VERSION 5.7 ;
BUSBITCHARS "[]" ;
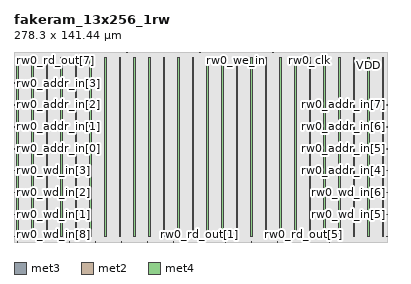
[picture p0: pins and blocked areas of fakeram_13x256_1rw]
MACRO fakeram_13x256_1rw
  FOREIGN fakeram_13x256_1rw 0 0 ;
  SYMMETRY X Y R90 ;
  SIZE 278.300 BY 141.440 ;
  CLASS BLOCK ;
  PIN rw0_wd_in[0]
    DIRECTION INPUT ;
    USE SIGNAL ;
    SHAPE ABUTMENT ;
    PORT
      LAYER met3 ;
      RECT 0.000 3.930 0.900 4.230 ;
    END
  END rw0_wd_in[0]
  PIN rw0_wd_in[1]
    DIRECTION INPUT ;
    USE SIGNAL ;
    SHAPE ABUTMENT ;
    PORT
      LAYER met3 ;
      RECT 0.000 20.250 0.900 20.550 ;
    END
  END rw0_wd_in[1]
  PIN rw0_wd_in[2]
    DIRECTION INPUT ;
    USE SIGNAL ;
    SHAPE ABUTMENT ;
    PORT
      LAYER met3 ;
      RECT 0.000 36.570 0.900 36.870 ;
    END
  END rw0_wd_in[2]
  PIN rw0_wd_in[3]
    DIRECTION INPUT ;
    USE SIGNAL ;
    SHAPE ABUTMENT ;
    PORT
      LAYER met3 ;
      RECT 0.000 52.890 0.900 53.190 ;
    END
  END rw0_wd_in[3]
  PIN rw0_wd_in[4]
    DIRECTION INPUT ;
    USE SIGNAL ;
    SHAPE ABUTMENT ;
    PORT
      LAYER met3 ;
      RECT 277.400 3.930 278.300 4.230 ;
    END
  END rw0_wd_in[4]
  PIN rw0_wd_in[5]
    DIRECTION INPUT ;
    USE SIGNAL ;
    SHAPE ABUTMENT ;
    PORT
      LAYER met3 ;
      RECT 277.400 20.250 278.300 20.550 ;
    END
  END rw0_wd_in[5]
  PIN rw0_wd_in[6]
    DIRECTION INPUT ;
    USE SIGNAL ;
    SHAPE ABUTMENT ;
    PORT
      LAYER met3 ;
      RECT 277.400 36.570 278.300 36.870 ;
    END
  END rw0_wd_in[6]
  PIN rw0_wd_in[7]
    DIRECTION INPUT ;
    USE SIGNAL ;
    SHAPE ABUTMENT ;
    PORT
      LAYER met2 ;
      RECT 2.690 0.000 2.830 0.420 ;
    END
  END rw0_wd_in[7]
  PIN rw0_wd_in[8]
    DIRECTION INPUT ;
    USE SIGNAL ;
    SHAPE ABUTMENT ;
    PORT
      LAYER met2 ;
      RECT 22.010 0.000 22.150 0.420 ;
    END
  END rw0_wd_in[8]
  PIN rw0_wd_in[9]
    DIRECTION INPUT ;
    USE SIGNAL ;
    SHAPE ABUTMENT ;
    PORT
      LAYER met2 ;
      RECT 41.330 0.000 41.470 0.420 ;
    END
  END rw0_wd_in[9]
  PIN rw0_wd_in[10]
    DIRECTION INPUT ;
    USE SIGNAL ;
    SHAPE ABUTMENT ;
    PORT
      LAYER met2 ;
      RECT 60.650 0.000 60.790 0.420 ;
    END
  END rw0_wd_in[10]
  PIN rw0_wd_in[11]
    DIRECTION INPUT ;
    USE SIGNAL ;
    SHAPE ABUTMENT ;
    PORT
      LAYER met2 ;
      RECT 79.970 0.000 80.110 0.420 ;
    END
  END rw0_wd_in[11]
  PIN rw0_wd_in[12]
    DIRECTION INPUT ;
    USE SIGNAL ;
    SHAPE ABUTMENT ;
    PORT
      LAYER met2 ;
      RECT 99.290 0.000 99.430 0.420 ;
    END
  END rw0_wd_in[12]
  PIN rw0_rd_out[0]
    DIRECTION OUTPUT ;
    USE SIGNAL ;
    SHAPE ABUTMENT ;
    PORT
      LAYER met2 ;
      RECT 118.610 0.000 118.750 0.420 ;
    END
  END rw0_rd_out[0]
  PIN rw0_rd_out[1]
    DIRECTION OUTPUT ;
    USE SIGNAL ;
    SHAPE ABUTMENT ;
    PORT
      LAYER met2 ;
      RECT 137.930 0.000 138.070 0.420 ;
    END
  END rw0_rd_out[1]
  PIN rw0_rd_out[2]
    DIRECTION OUTPUT ;
    USE SIGNAL ;
    SHAPE ABUTMENT ;
    PORT
      LAYER met2 ;
      RECT 157.250 0.000 157.390 0.420 ;
    END
  END rw0_rd_out[2]
  PIN rw0_rd_out[3]
    DIRECTION OUTPUT ;
    USE SIGNAL ;
    SHAPE ABUTMENT ;
    PORT
      LAYER met2 ;
      RECT 176.570 0.000 176.710 0.420 ;
    END
  END rw0_rd_out[3]
  PIN rw0_rd_out[4]
    DIRECTION OUTPUT ;
    USE SIGNAL ;
    SHAPE ABUTMENT ;
    PORT
      LAYER met2 ;
      RECT 195.890 0.000 196.030 0.420 ;
    END
  END rw0_rd_out[4]
  PIN rw0_rd_out[5]
    DIRECTION OUTPUT ;
    USE SIGNAL ;
    SHAPE ABUTMENT ;
    PORT
      LAYER met2 ;
      RECT 215.210 0.000 215.350 0.420 ;
    END
  END rw0_rd_out[5]
  PIN rw0_rd_out[6]
    DIRECTION OUTPUT ;
    USE SIGNAL ;
    SHAPE ABUTMENT ;
    PORT
      LAYER met2 ;
      RECT 234.530 0.000 234.670 0.420 ;
    END
  END rw0_rd_out[6]
  PIN rw0_rd_out[7]
    DIRECTION OUTPUT ;
    USE SIGNAL ;
    SHAPE ABUTMENT ;
    PORT
      LAYER met2 ;
      RECT 2.690 141.020 2.830 141.440 ;
    END
  END rw0_rd_out[7]
  PIN rw0_rd_out[8]
    DIRECTION OUTPUT ;
    USE SIGNAL ;
    SHAPE ABUTMENT ;
    PORT
      LAYER met2 ;
      RECT 29.830 141.020 29.970 141.440 ;
    END
  END rw0_rd_out[8]
  PIN rw0_rd_out[9]
    DIRECTION OUTPUT ;
    USE SIGNAL ;
    SHAPE ABUTMENT ;
    PORT
      LAYER met2 ;
      RECT 56.970 141.020 57.110 141.440 ;
    END
  END rw0_rd_out[9]
  PIN rw0_rd_out[10]
    DIRECTION OUTPUT ;
    USE SIGNAL ;
    SHAPE ABUTMENT ;
    PORT
      LAYER met2 ;
      RECT 84.110 141.020 84.250 141.440 ;
    END
  END rw0_rd_out[10]
  PIN rw0_rd_out[11]
    DIRECTION OUTPUT ;
    USE SIGNAL ;
    SHAPE ABUTMENT ;
    PORT
      LAYER met2 ;
      RECT 111.250 141.020 111.390 141.440 ;
    END
  END rw0_rd_out[11]
  PIN rw0_rd_out[12]
    DIRECTION OUTPUT ;
    USE SIGNAL ;
    SHAPE ABUTMENT ;
    PORT
      LAYER met2 ;
      RECT 138.390 141.020 138.530 141.440 ;
    END
  END rw0_rd_out[12]
  PIN rw0_addr_in[0]
    DIRECTION INPUT ;
    USE SIGNAL ;
    SHAPE ABUTMENT ;
    PORT
      LAYER met3 ;
      RECT 0.000 69.210 0.900 69.510 ;
    END
  END rw0_addr_in[0]
  PIN rw0_addr_in[1]
    DIRECTION INPUT ;
    USE SIGNAL ;
    SHAPE ABUTMENT ;
    PORT
      LAYER met3 ;
      RECT 0.000 85.530 0.900 85.830 ;
    END
  END rw0_addr_in[1]
  PIN rw0_addr_in[2]
    DIRECTION INPUT ;
    USE SIGNAL ;
    SHAPE ABUTMENT ;
    PORT
      LAYER met3 ;
      RECT 0.000 101.850 0.900 102.150 ;
    END
  END rw0_addr_in[2]
  PIN rw0_addr_in[3]
    DIRECTION INPUT ;
    USE SIGNAL ;
    SHAPE ABUTMENT ;
    PORT
      LAYER met3 ;
      RECT 0.000 118.170 0.900 118.470 ;
    END
  END rw0_addr_in[3]
  PIN rw0_addr_in[4]
    DIRECTION INPUT ;
    USE SIGNAL ;
    SHAPE ABUTMENT ;
    PORT
      LAYER met3 ;
      RECT 277.400 52.890 278.300 53.190 ;
    END
  END rw0_addr_in[4]
  PIN rw0_addr_in[5]
    DIRECTION INPUT ;
    USE SIGNAL ;
    SHAPE ABUTMENT ;
    PORT
      LAYER met3 ;
      RECT 277.400 69.210 278.300 69.510 ;
    END
  END rw0_addr_in[5]
  PIN rw0_addr_in[6]
    DIRECTION INPUT ;
    USE SIGNAL ;
    SHAPE ABUTMENT ;
    PORT
      LAYER met3 ;
      RECT 277.400 85.530 278.300 85.830 ;
    END
  END rw0_addr_in[6]
  PIN rw0_addr_in[7]
    DIRECTION INPUT ;
    USE SIGNAL ;
    SHAPE ABUTMENT ;
    PORT
      LAYER met3 ;
      RECT 277.400 101.850 278.300 102.150 ;
    END
  END rw0_addr_in[7]
  PIN rw0_we_in
    DIRECTION INPUT ;
    USE SIGNAL ;
    SHAPE ABUTMENT ;
    PORT
      LAYER met2 ;
      RECT 165.530 141.020 165.670 141.440 ;
    END
  END rw0_we_in
  PIN rw0_ce_in
    DIRECTION INPUT ;
    USE SIGNAL ;
    SHAPE ABUTMENT ;
    PORT
      LAYER met2 ;
      RECT 192.670 141.020 192.810 141.440 ;
    END
  END rw0_ce_in
  PIN rw0_clk
    DIRECTION INPUT ;
    USE SIGNAL ;
    SHAPE ABUTMENT ;
    PORT
      LAYER met2 ;
      RECT 219.810 141.020 219.950 141.440 ;
    END
  END rw0_clk
  PIN VSS
    DIRECTION INOUT ;
    USE GROUND ;
    PORT
      LAYER met4 ;
      RECT 2.160 4.080 3.360 137.360 ;
      RECT 13.040 4.080 14.240 137.360 ;
      RECT 23.920 4.080 25.120 137.360 ;
      RECT 34.800 4.080 36.000 137.360 ;
      RECT 45.680 4.080 46.880 137.360 ;
      RECT 56.560 4.080 57.760 137.360 ;
      RECT 67.440 4.080 68.640 137.360 ;
      RECT 78.320 4.080 79.520 137.360 ;
      RECT 89.200 4.080 90.400 137.360 ;
      RECT 100.080 4.080 101.280 137.360 ;
      RECT 110.960 4.080 112.160 137.360 ;
      RECT 121.840 4.080 123.040 137.360 ;
      RECT 132.720 4.080 133.920 137.360 ;
      RECT 143.600 4.080 144.800 137.360 ;
      RECT 154.480 4.080 155.680 137.360 ;
      RECT 165.360 4.080 166.560 137.360 ;
      RECT 176.240 4.080 177.440 137.360 ;
      RECT 187.120 4.080 188.320 137.360 ;
      RECT 198.000 4.080 199.200 137.360 ;
      RECT 208.880 4.080 210.080 137.360 ;
      RECT 219.760 4.080 220.960 137.360 ;
      RECT 230.640 4.080 231.840 137.360 ;
      RECT 241.520 4.080 242.720 137.360 ;
      RECT 252.400 4.080 253.600 137.360 ;
      RECT 263.280 4.080 264.480 137.360 ;
      RECT 274.160 4.080 275.360 137.360 ;
    END
  END VSS
  PIN VDD
    DIRECTION INOUT ;
    USE POWER ;
    PORT
      LAYER met4 ;
      RECT 2.160 4.080 3.360 137.360 ;
      RECT 13.040 4.080 14.240 137.360 ;
      RECT 23.920 4.080 25.120 137.360 ;
      RECT 34.800 4.080 36.000 137.360 ;
      RECT 45.680 4.080 46.880 137.360 ;
      RECT 56.560 4.080 57.760 137.360 ;
      RECT 67.440 4.080 68.640 137.360 ;
      RECT 78.320 4.080 79.520 137.360 ;
      RECT 89.200 4.080 90.400 137.360 ;
      RECT 100.080 4.080 101.280 137.360 ;
      RECT 110.960 4.080 112.160 137.360 ;
      RECT 121.840 4.080 123.040 137.360 ;
      RECT 132.720 4.080 133.920 137.360 ;
      RECT 143.600 4.080 144.800 137.360 ;
      RECT 154.480 4.080 155.680 137.360 ;
      RECT 165.360 4.080 166.560 137.360 ;
      RECT 176.240 4.080 177.440 137.360 ;
      RECT 187.120 4.080 188.320 137.360 ;
      RECT 198.000 4.080 199.200 137.360 ;
      RECT 208.880 4.080 210.080 137.360 ;
      RECT 219.760 4.080 220.960 137.360 ;
      RECT 230.640 4.080 231.840 137.360 ;
      RECT 241.520 4.080 242.720 137.360 ;
      RECT 252.400 4.080 253.600 137.360 ;
      RECT 263.280 4.080 264.480 137.360 ;
      RECT 274.160 4.080 275.360 137.360 ;
    END
  END VDD
  OBS
    LAYER met1 ;
    RECT 0 0 278.300 141.440 ;
    LAYER met2 ;
    RECT 0 0 278.300 141.440 ;
    LAYER met3 ;
    RECT 0 0 278.300 141.440 ;
    LAYER met4 ;
    RECT 0 0 278.300 141.440 ;
  END
END fakeram_13x256_1rw

END LIBRARY
